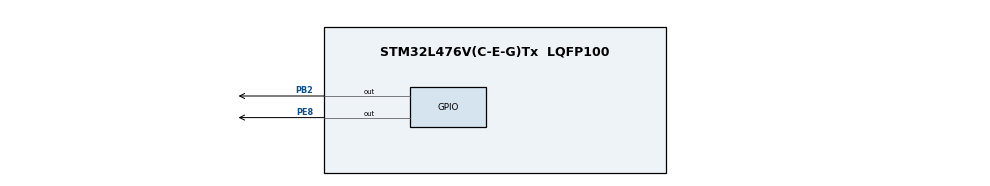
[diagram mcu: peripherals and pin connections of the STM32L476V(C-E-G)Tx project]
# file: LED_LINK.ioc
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Mcu.Family=STM32L4
Mcu.Name=STM32L476V(C-E-G)Tx
Mcu.Package=LQFP100
NVIC.PriorityGroup=NVIC_PRIORITYGROUP_4
PB2.Signal=GPIO_Output
PE8.Signal=GPIO_Output
ProjectManager.HeapSize=0x200
ProjectManager.StackSize=0x400
ProjectManager.TargetToolchain=SW4STM32
RCC.HSE_VALUE=8000000
RCC.HSI_VALUE=16000000
RCC.LSE_VALUE=32768
RCC.MSI_VALUE=4000000
RCC.VCOOutputFreq_Value=32000000
board=custom

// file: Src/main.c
/* USER CODE BEGIN Header */
/**
  ******************************************************************************
  * @file           : main.c
  * @brief          : Main program body
  ******************************************************************************
  * @attention
  *
  * <h2><center>&copy; Copyright (c) 2019 STMicroelectronics.
  * All rights reserved.</center></h2>
  *
  * This software component is licensed by ST under BSD 3-Clause license,
  * the "License"; You may not use this file except in compliance with the
  * License. You may obtain a copy of the License at:
  *                        opensource.org/licenses/BSD-3-Clause
  *
  ******************************************************************************
  */
/* USER CODE END Header */

#include "main.h"

//
__attribute__((__section__(".user_data"))) uint8_t RefMAC[16]={0xaf,0x7a,0xe2,0x89,0x9f,0xb7,0x20,0xff,0xd5,0xc3,0x0c,0xba,0x08,0x71,0x8d,0x8b};

__attribute__((__section__(".length_application"))) uint32_t length_app = 6240;

extern uint32_t _stext;
extern uint32_t _etext;
uint32_t length_1 = 0;

void SystemClock_Config(void);
static void MX_GPIO_Init(void);

int main(void)
{
	length_1 = &_etext - &_stext;

  /* MCU Configuration--------------------------------------------------------*/

  /* Reset of all peripherals, Initializes the Flash interface and the Systick. */
  HAL_Init();

  /* Configure the system clock */
  SystemClock_Config();

  /* Initialize all configured peripherals */
  MX_GPIO_Init();

  /* Infinite loop */
  /* USER CODE BEGIN WHILE */
  uint32_t i = 0;

  while (1)
  {
    /* USER CODE END WHILE */

	  HAL_GPIO_TogglePin(GPIOB, GPIO_PIN_2);
	  for(i =0; i< 3000000; i++)
	  	  {

	  	  }
	  HAL_GPIO_TogglePin(GPIOE, GPIO_PIN_8);

	  for(i =0; i< 3000000; i++)
	  {

	  }

	  //HAL_Delay(500);
  }
}

void SystemClock_Config(void)
{
  RCC_OscInitTypeDef RCC_OscInitStruct = {0};
  RCC_ClkInitTypeDef RCC_ClkInitStruct = {0};
  RCC_PeriphCLKInitTypeDef PeriphClkInit = {0};

  /** Initializes the CPU, AHB and APB busses clocks
  */
  RCC_OscInitStruct.OscillatorType = RCC_OSCILLATORTYPE_HSI;
  RCC_OscInitStruct.HSIState = RCC_HSI_ON;
  RCC_OscInitStruct.HSICalibrationValue = RCC_HSICALIBRATION_DEFAULT;
  RCC_OscInitStruct.PLL.PLLState = RCC_PLL_ON;
  RCC_OscInitStruct.PLL.PLLSource = RCC_PLLSOURCE_HSI;
  RCC_OscInitStruct.PLL.PLLM = 1;
  RCC_OscInitStruct.PLL.PLLN = 20;
  RCC_OscInitStruct.PLL.PLLP = RCC_PLLP_DIV7;
  RCC_OscInitStruct.PLL.PLLQ = RCC_PLLQ_DIV2;
  RCC_OscInitStruct.PLL.PLLR = RCC_PLLR_DIV4;
  if (HAL_RCC_OscConfig(&RCC_OscInitStruct) != HAL_OK)
  {
    Error_Handler();
  }
  /** Initializes the CPU, AHB and APB busses clocks
  */
  RCC_ClkInitStruct.ClockType = RCC_CLOCKTYPE_HCLK|RCC_CLOCKTYPE_SYSCLK
                              |RCC_CLOCKTYPE_PCLK1|RCC_CLOCKTYPE_PCLK2;
  RCC_ClkInitStruct.SYSCLKSource = RCC_SYSCLKSOURCE_PLLCLK;
  RCC_ClkInitStruct.AHBCLKDivider = RCC_SYSCLK_DIV1;
  RCC_ClkInitStruct.APB1CLKDivider = RCC_HCLK_DIV1;
  RCC_ClkInitStruct.APB2CLKDivider = RCC_HCLK_DIV1;

  if (HAL_RCC_ClockConfig(&RCC_ClkInitStruct, FLASH_LATENCY_4) != HAL_OK)
  {
    Error_Handler();
  }
  PeriphClkInit.PeriphClockSelection = RCC_PERIPHCLK_USART2;
  PeriphClkInit.Usart2ClockSelection = RCC_USART2CLKSOURCE_PCLK1;
  if (HAL_RCCEx_PeriphCLKConfig(&PeriphClkInit) != HAL_OK)
  {
    Error_Handler();
  }
  /** Configure the main internal regulator output voltage
  */
  if (HAL_PWREx_ControlVoltageScaling(PWR_REGULATOR_VOLTAGE_SCALE1) != HAL_OK)
  {
    Error_Handler();
  }
}

static void MX_GPIO_Init(void)
{
  GPIO_InitTypeDef GPIO_InitStruct = {0};

  /* GPIO Ports Clock Enable */
  __HAL_RCC_GPIOB_CLK_ENABLE();
  __HAL_RCC_GPIOE_CLK_ENABLE();

  /*Configure GPIO pin Output Level */
  HAL_GPIO_WritePin(GPIOB, GPIO_PIN_2, GPIO_PIN_RESET);

  /*Configure GPIO pin Output Level */
  HAL_GPIO_WritePin(GPIOE, GPIO_PIN_8, GPIO_PIN_RESET);

  /*Configure GPIO pin : PB2 */
  GPIO_InitStruct.Pin = GPIO_PIN_2;
  GPIO_InitStruct.Mode = GPIO_MODE_OUTPUT_PP;
  GPIO_InitStruct.Pull = GPIO_NOPULL;
  GPIO_InitStruct.Speed = GPIO_SPEED_FREQ_LOW;
  HAL_GPIO_Init(GPIOB, &GPIO_InitStruct);

  /*Configure GPIO pin : PE8 */
  GPIO_InitStruct.Pin = GPIO_PIN_8;
  GPIO_InitStruct.Mode = GPIO_MODE_OUTPUT_PP;
  GPIO_InitStruct.Pull = GPIO_NOPULL;
  GPIO_InitStruct.Speed = GPIO_SPEED_FREQ_LOW;
  HAL_GPIO_Init(GPIOE, &GPIO_InitStruct);

}

void Error_Handler(void)
{
}

/************************ (C) COPYRIGHT STMicroelectronics *****END OF FILE****/
